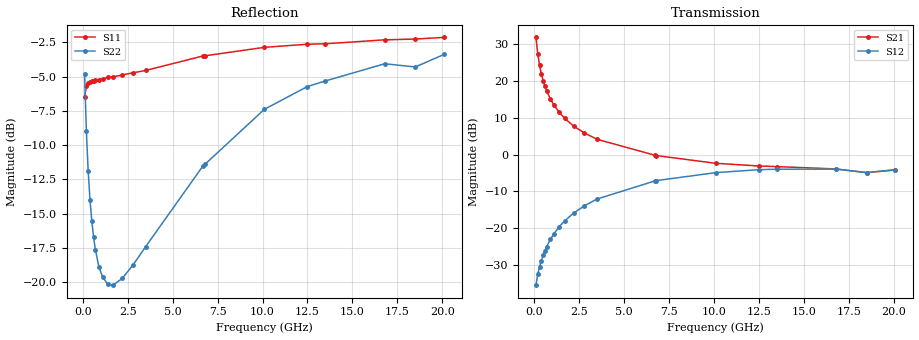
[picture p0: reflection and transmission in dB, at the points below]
!  Infineon Technologies AG
! BFR380L3 , PF131585-7, No.6, Th 09.10.01, soldered on pcb-board, measured with PP GSG850
!  Vce=3.5 V,  Ic=75.0 mA
! Common Emitter S-Parameters:  15. November 2001
#  GHz  S  MA  R  50
! f  S11  S21  S12  S22
! GHz  Mag  Ang  Mag  Ang  Mag  Ang  Mag  Ang
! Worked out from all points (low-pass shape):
!   201 points, 100 MHz to 20.1 GHz, reference 50 ohm
!   highest |S21| = 31.85 dB at 100 MHz (marker M1); lowest = -4.9 dB at 18.5 GHz (marker M2)
!   |S21| within 3 dB of the highest: start of sweep to 168.1 MHz
!   lowest |S11| = -6.5 dB at 100 MHz (marker M3), VSWR 2.79, Z = 25.4 - j29.3 ohm
!   |S11| at or under -10 dB: nowhere
!   |S22| runs from -20.2 to -3.4 dB; largest |S21 - S12| = 39
!   S11 on the Smith chart (normalised r, x): 100 MHz: 0.51, -0.59; 400 MHz: 0.30, -0.13; 2.8 GHz: 0.29, +0.29; 6.7 GHz: 0.33, +0.78; 12.5 GHz: 0.53, +1.52; 20.1 GHz: 1.04, +2.56
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0.1  0.473 -108.8  39.14 129.3  0.01676 59.4  0.5776 -49.9
0.2  0.5213 -142.1  23.57 110.2  0.02351 57.5  0.355 -68.2
0.3  0.5352 -156.1  16.46 101.7  0.0296 60.9  0.2542 -76.2
0.4  0.5394 -164.1  12.57 96.3  0.03599 63.5  0.1999 -81.3
0.5  0.5428 -169.9  10.14 92.4  0.04254 66.3  0.1674 -85.1
0.6  0.5435 -174.0  8.497 89.4  0.04928 67.7  0.1462 -88.1
0.7  0.5462 -177.4  7.319 86.7  0.05602 68.7  0.1315 -91.0
0.9  0.5491 177.1  5.728 82.2  0.06995 69.9  0.1135 -95.8
1.1  0.553 172.5  4.717 78.3  0.08377 70.3  0.1046 -100.7
1.4  0.5589 166.7  3.735 72.9  0.1046 70.0  0.09811 -107.4
1.7  0.5615 161.4  3.1 68.0  0.1255 69.0  0.09759 -114.1
2.2  0.5712 153.5  2.435 60.4  0.16 66.7  0.1034 -124.5
2.8  0.5812 144.7  1.96 51.9  0.2009 63.2  0.1157 -136.3
3.5  0.5929 135.3  1.611 42.8  0.2483 58.6  0.1349 -147.1
6.7  0.6698 100.5  0.9806 11.1  0.4359 35.8  0.2664 164.6
6.8  0.6705 99.5  0.9677 10.3  0.4417 35.0  0.2695 163.2
10.1  0.7199 74.9  0.7601 -8.8  0.5671 12.3  0.4274 128.7
12.5  0.739 62.3  0.6984 -19.0  0.622 -3.1  0.518 106.9
13.5  0.7418 58.0  0.6849 -22.9  0.6312 -9.2  0.5427 99.6
16.8  0.7667 46.1  0.6365 -33.4  0.6325 -25.4  0.6271 77.6
18.5  0.7718 44.4  0.5672 -40.7  0.5685 -33.7  0.6105 72.0
20.1  0.7827 37.6  0.6158 -43.9  0.623 -39.1  0.678 61.1
